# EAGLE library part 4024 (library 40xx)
7-stage binary/ripple COUNTER

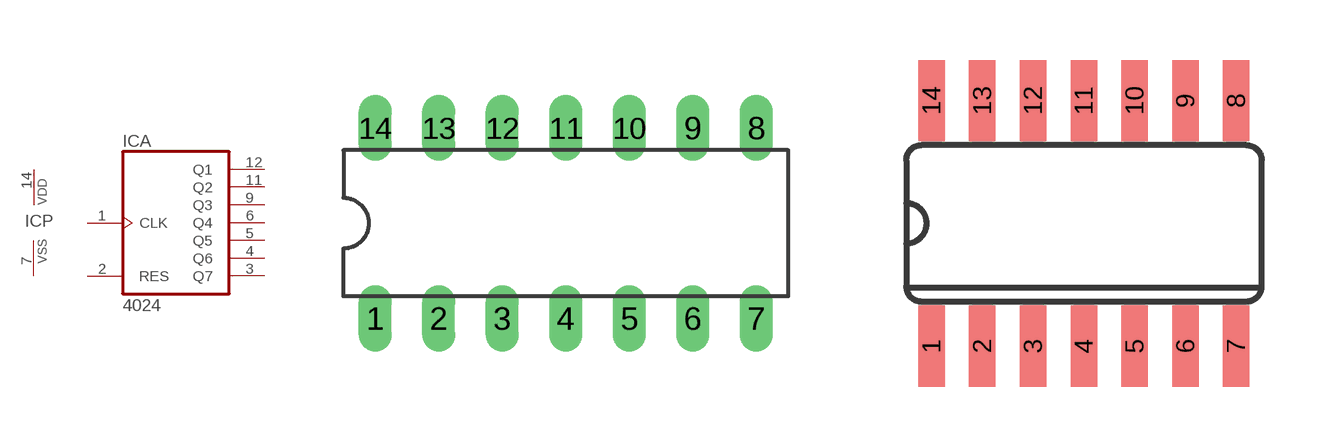
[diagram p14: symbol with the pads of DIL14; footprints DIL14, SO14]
Designator prefix IC; gates A=4024 P=PWRN

## 4024N  [DIL14]
1  A:CLK  in
2  A:RES  in
3  A:Q7  out
4  A:Q6  out
5  A:Q5  out
6  A:Q4  out
7  P:VSS  pwr
9  A:Q3  out
11  A:Q2  out
12  A:Q1  out
14  P:VDD  pwr

## 4024D  [SO14]
Pads as for DIL14

## Footprint DIL14 (pad centres in mm)
Dual In Line Package
drill 0.813 long: 1 -7.62,-3.81; 2 -5.08,-3.81; 3 -2.54,-3.81; 4 0,-3.81; 5 2.54,-3.81; 6 5.08,-3.81; 7 7.62,-3.81; 8 7.62,3.81; 9 5.08,3.81; 10 2.54,3.81; 11 0,3.81; 12 -2.54,3.81; 13 -5.08,3.81; 14 -7.62,3.81

## Footprint SO14 (pad centres in mm)
Small Outline package 150 mil
smd 0.66 x 2.032: 1 -3.81,-3.073; 2 -2.54,-3.073; 3 -1.27,-3.073; 4 0,-3.073; 5 1.27,-3.073; 6 2.54,-3.073; 7 3.81,-3.073; 8 3.81,3.073; 9 2.54,3.073; 10 1.27,3.073; 11 0,3.073; 12 -1.27,3.073; 13 -2.54,3.073; 14 -3.81,3.073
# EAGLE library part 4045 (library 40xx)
21 -Stage Counter Source: www.radanpro.com/el/datasheets_cmos.htm cd_4045.pdf Type Manufatk. 4045BDCFCH 4045BDMFCH 40458BFCFCH 4045BFMFCH 4045BPCFCH CD4045ADRCA CD4045AERCA CD4045AFRCA CD4045AHRCA CD4045AKRCA CD4045BDRCA CD4045BERCA CD4045BFRCA CD4045BHRCA CD045BKSCA HCC4045BDSCA HCC4045BFSGS HCC4045BKSGS HCF4045BESGS HCF4045BFSGS

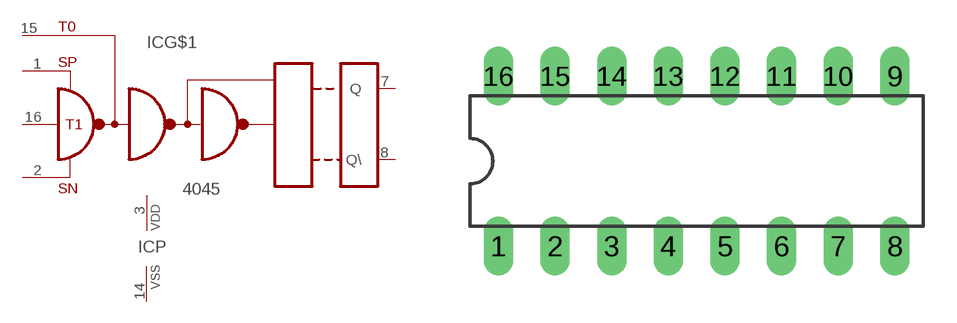
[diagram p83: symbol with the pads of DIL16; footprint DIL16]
Designator prefix IC; gates G$1=4045 P=PWRN

## 4045  [DIL16]
1  G$1:SP  in
2  G$1:SN  in
3  P:VDD  pwr
7  G$1:Q  in
8  G$1:Q\  in
14  P:VSS  pwr
15  G$1:T0  in
16  G$1:T1  in

## Footprint DIL16 (pad centres in mm)
Dual In Line Package
drill 0.813 long: 1 -8.89,-3.81; 2 -6.35,-3.81; 3 -3.81,-3.81; 4 -1.27,-3.81; 5 1.27,-3.81; 6 3.81,-3.81; 7 6.35,-3.81; 8 8.89,-3.81; 9 8.89,3.81; 10 6.35,3.81; 11 3.81,3.81; 12 1.27,3.81; 13 -1.27,3.81; 14 -3.81,3.81; 15 -6.35,3.81; 16 -8.89,3.81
